VERSION 5.7 ;
  NOWIREEXTENSIONATPIN ON ;
  DIVIDERCHAR "/" ;
  BUSBITCHARS "[]" ;
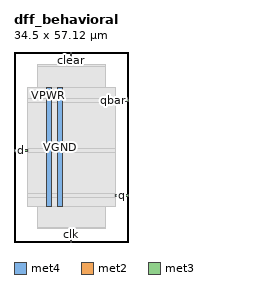
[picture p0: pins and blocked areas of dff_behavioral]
MACRO dff_behavioral
  CLASS BLOCK ;
  FOREIGN dff_behavioral ;
  ORIGIN 0.000 0.000 ;
  SIZE 34.500 BY 57.120 ;
  PIN VGND
    DIRECTION INOUT ;
    USE GROUND ;
    PORT
      LAYER met4 ;
        RECT 13.020 10.640 14.620 46.480 ;
    END
  END VGND
  PIN VPWR
    DIRECTION INOUT ;
    USE POWER ;
    PORT
      LAYER met4 ;
        RECT 9.720 10.640 11.320 46.480 ;
    END
  END VPWR
  PIN clear
    DIRECTION INPUT ;
    USE SIGNAL ;
    ANTENNAGATEAREA 0.196500 ;
    PORT
      LAYER met2 ;
        RECT 17.110 53.120 17.390 57.120 ;
    END
  END clear
  PIN clk
    DIRECTION INPUT ;
    USE SIGNAL ;
    ANTENNAGATEAREA 0.852000 ;
    PORT
      LAYER met2 ;
        RECT 17.110 0.000 17.390 4.000 ;
    END
  END clk
  PIN d
    DIRECTION INPUT ;
    USE SIGNAL ;
    ANTENNAGATEAREA 0.196500 ;
    PORT
      LAYER met3 ;
        RECT 0.000 27.240 4.000 27.840 ;
    END
  END d
  PIN q
    DIRECTION OUTPUT ;
    USE SIGNAL ;
    ANTENNADIFFAREA 0.340600 ;
    PORT
      LAYER met3 ;
        RECT 30.500 13.640 34.500 14.240 ;
    END
  END q
  PIN qbar
    DIRECTION OUTPUT ;
    USE SIGNAL ;
    ANTENNADIFFAREA 0.340600 ;
    PORT
      LAYER met3 ;
        RECT 30.500 42.200 34.500 42.800 ;
    END
  END qbar
  OBS
      LAYER nwell ;
        RECT 5.330 10.795 29.170 46.430 ;
      LAYER li1 ;
        RECT 5.520 10.795 28.980 46.325 ;
      LAYER met1 ;
        RECT 5.520 10.640 28.980 46.480 ;
      LAYER met2 ;
        RECT 6.990 52.840 16.830 53.450 ;
        RECT 17.670 52.840 27.510 53.450 ;
        RECT 6.990 4.280 27.510 52.840 ;
        RECT 6.990 4.000 16.830 4.280 ;
        RECT 17.670 4.000 27.510 4.280 ;
      LAYER met3 ;
        RECT 4.000 43.200 30.500 46.405 ;
        RECT 4.000 41.800 30.100 43.200 ;
        RECT 4.000 28.240 30.500 41.800 ;
        RECT 4.400 26.840 30.500 28.240 ;
        RECT 4.000 14.640 30.500 26.840 ;
        RECT 4.000 13.240 30.100 14.640 ;
        RECT 4.000 10.715 30.500 13.240 ;
  END
END dff_behavioral
END LIBRARY

